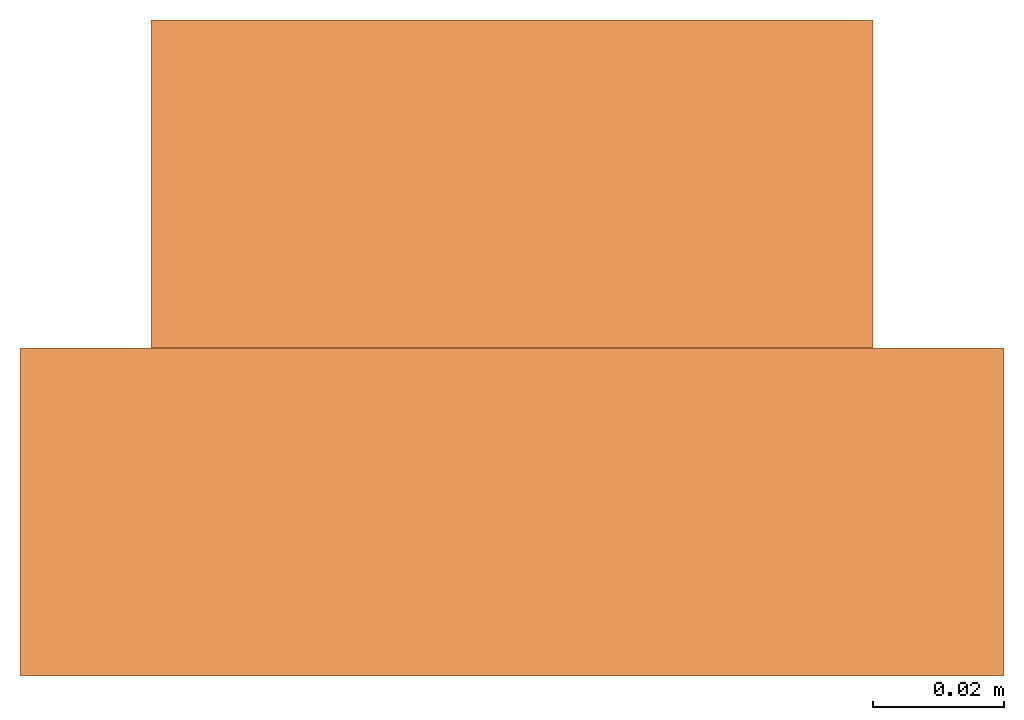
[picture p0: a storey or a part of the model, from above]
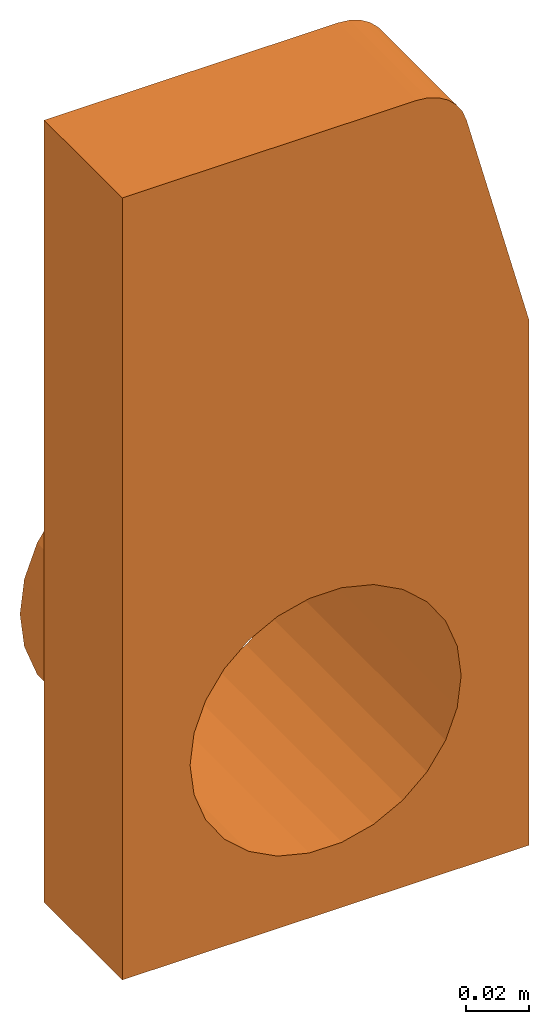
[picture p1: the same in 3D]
Properties of the parts of a building model (IFC2X3)

# File
Description: ViewDefinition [CoordinationView]
File name: 7964 - LH inlet or outlet end cap.ifc
Time: 2013-09-12T12:44:01
Written by: Autodesk Revit 2013
Made in: 20120221_2030(x64)

# IfcProject, Project Number
LongName: Project Name; Phase: Project Status

# IfcSite, Default
RefLatitude: 42, 21, 30, 344238; RefLongitude: -71, -3, -35, -194702; RefElevation: 0 mm

# IfcBuilding
Pset_BuildingCommon - NumberOfStoreys: 2
Other - Project Status: Project Status; Project Address: Enter address here; Client Name: Owner; Project Issue Date: Issue Date; Project Number: Project Number; Project Name: Project Name

# IfcBuildingStorey (2)
Constraints - Elevation Base: 0
Graphics - Symbol: M_Level Head - Circle: M_Level Head - Circle; Color: 0; Symbol at End 2 Default: yes; Line Weight: 1; Line Pattern: Center; Symbol at End 1 Default: no
Dimensions - Computation Height: 0 mm
Identity Data - Structural: no; Building Story: yes
Name | LongName = Name | Elevation (mm) = Constraints, Elevation (mm)
T.O. Fnd. Wall | T.O. Fnd. Wall | -300
Level 1 | Level 1 | 0

# IfcBuildingElementProxy: 7964 - LH inlet/outlet end cap, Civil-Drainage-Channel-ACO-KerbDrain-HB305 - PART 1:7964 - LH inlet/outlet end cap:7964 - LH inlet/outlet end cap:255899
In: T.O. Fnd. Wall
Material: Orange, ACO Polymer Concrete.
Materials and Finishes - Access Cover/Frame Colour: N/A; Channel Colour: N/A; Connection Pipe Material: PVCu; Channel Material: N/A; Access Cover/Frame Finish: N/A; Connection Pipe Material Colour: Brown; End Cap Material: Vienite® Synthetic Resin Concrete; Access Cover/Frame Material: N/A; End Cap Colour: Grey
Construction - KDHB305 - Channel unit - 500mm: no; KDHB305 - RH Inlet/outlet end cap: no; KDHB305 - Centre stone: no; KDHB305 - Channel unit - 1000mm: no; KDHB305 - Drainable centre stone: no; KDHB305 - LH drop kerb: no; KDHB305 - Perforated centre stone: no; KDHB305 - Flush RH dropkerb: no; KDHB305 - Channel unit - 250mm: no; KDHB305 - Access Unit: no; KDHB305 - Closing end cap: no; KDHB305 - LH Inlet/Outlet end cap: yes; KDHB305 - RH drop kerb: no; I/O Pipe: yes; KDHB305 - Flush LH dropkerb: no; KDHB305 - Blind unit: no
Dimensions - I/O Endcap Void depth: 230.003 mm; Void_Width: 150 mm; Staright Void Depth: -180 mm; Void_Length: 50 mm; Volume: 1908258 mm3
Constraints - Moves With Nearby Elements: no; Level: Level: Level 1
Phasing - Phase Created: Phase 1
Pset_BuildingElementProxyCommon - Reference: 7964 - LH inlet/outlet end cap
Data - Drainage Slot Width: N/A; Product Dimensions: 50mm x 150mm x 305mm (LxWxH); Drainage Slot Intake area: N/A; Installation - Concrete Grade: N/A; Concrete Surround Volume - Load Class A 15 - D 400 - Grass or Asphalt Pavement: N/A; Invert Depth: N/A; Product Weight: 3.9 Kg; Product Standard: N/A; Load Class: N/A; Connection Pipe O.D: Ø110mm; Channel C.S.A: N/A; ACO Hydraulic Design Software: N/A; Concrete Surround Volume - Load Class A 15 - D 400 - Concrete Pavement: N/A; Hydraulic Performance: N/A
Identity Data - Product Page URL: http://www.aco.co.uk/product_detail.php?id=3; Fax: +44 (0)1462 815895; Assembly Description: Rain Water Drainage; OmniClass Number: 23.70.50.24; Product brochure: http://www.aco.co.uk/download.php?id=120; Address: ACO Business Park, Hitchin Road, Shefford, Bedfordshire, United Kingdom SG17 5TE; URL: www.aco.co.uk; E-mail Sales: customersupport@aco.co.uk; OmniClass Title: Rainwater Removal; Manufacturer: ACO Technologies plc - ACO Water Management Division; Product Code: 7964; Model Description: Combined kerb and drainage system; E-mail Technical: technical@aco.co.uk; Installation guidelines: http://www.aco.co.uk/download.php?id=120; Price: POA - contact ACO; Model: ACO KerbDrain HB305; Maintenance guidelines: http://www.aco.co.uk/download.php?id=120; Cost: 0; Telephone: +44 (0)1462 816666; Type Comments: ACO KerbDrain HB305 half battered LH outlet end cap; Assembly Code: D2040
General - SerialNumber: 0.000000; TagNumber: 0.000000
Green Building Properties - End Cap Recycled Material Content: 20% minimum; Access Cover/Frame Recyclable: N/A; End Cap Recyclable: Fully recyclable; Channel Recycled Material Content: N/A; Channel Recyclable: N/A; Access Cover/Frame Recycled Material Content: N/A
Other - Revision: 1; CreatedBy: www.aco.co.uk

# IfcOpeningElement: Recess
In: Level 1
Constraints - Level: Level: Level 1; Room Bounding: yes; Height Offset From Level: 0 mm; Related to Mass: no
Phasing - Phase Created: Phase 1
Structural - Structural: no; Enable Analytical Model: no
Dimensions - Volume: 21204611067 mm3; Area: 53016081 mm2; Perimeter: 29157.2 mm; Thickness: 400 mm
Graphics - Coarse Scale Fill Color: 0
Analytical Properties - Roughness: 1; Absorptance: 0.1
Construction - Default Thickness: 400 mm; Function: 0

# IfcSlab: Floor:Generic Floor - 400mm, Floor:Generic Floor - 400mm:184025
In: Level 1
PredefinedType: FLOOR; Material: Default Floor 400 mm
Constraints - Level: Level: Level 1; Room Bounding: yes; Height Offset From Level: 0 mm; Related to Mass: no
Phasing - Phase Created: Phase 1
Structural - Structural: no; Enable Analytical Model: no
Dimensions - Volume: 21204611067 mm3; Area: 53016081 mm2; Perimeter: 29157.2 mm; Thickness: 400 mm
Pset_SlabCommon - Reference: Generic Floor - 400mm; IsExternal: no; LoadBearing: yes
Graphics - Coarse Scale Fill Color: 0
Analytical Properties - Roughness: 1; Absorptance: 0.1
Construction - Default Thickness: 400 mm; Function: 0
